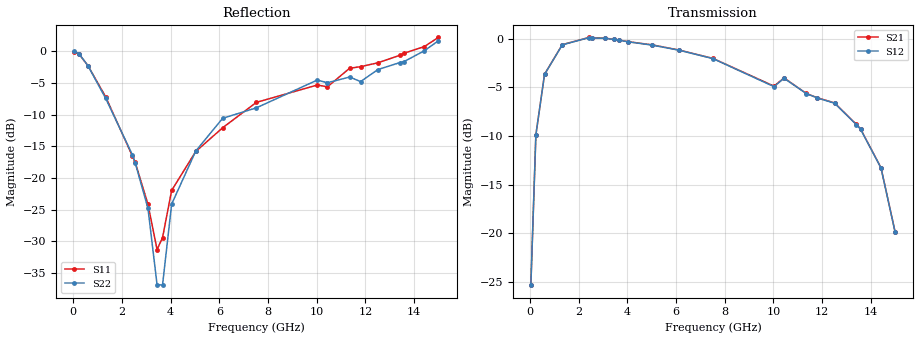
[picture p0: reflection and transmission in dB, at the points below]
! VJ1111D2R2BXR
! DATE 03/08/2022  10:55
! CAPACITORS MOUNTED IN SERIES ON 25 MIL THICK MICROSTRIP SUBSTRATE
# GHz  S  MA  R  50.00
!  FREQ  S11M  S11A  S21M  S21A  S12M  S12A  S22M  S22A
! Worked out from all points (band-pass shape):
!   801 points, 40 MHz to 15 GHz, reference 50 ohm
!   highest |S21| = 0.13 dB at 2.434 GHz (marker M1); lowest = -25.3 dB at 40 MHz (marker M2)
!   |S21| within 3 dB of the highest: 700.3 MHz to 8.719 GHz (8.019 GHz wide, 170 % of centre)
!   lowest |S11| = -31.3 dB at 3.443 GHz (marker M3), VSWR 1.06, Z = 47.7 - j1.24 ohm
!   |S11| at or under -10 dB: 1.71 GHz to 6.915 GHz (5.205 GHz wide, 121 % of centre)
!   |S22| runs from -38.9 to 1.7 dB; largest |S21 - S12| = 0.007
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0.04  0.9961 -3.1  0.05424 86.5  0.05463 86.1  1.004 -3.1
0.2457  0.9471 -18.2  0.3207 72.2  0.3207 72.3  0.9537 -18.2
0.601  0.7733 -39.9  0.6562 51.6  0.6551 51.6  0.773 -39.9
1.3303  0.4383 -65.6  0.9315 28.0  0.9291 28.0  0.4261 -66.8
2.4336  0.1483 -85.1  1.015 12.4  1.013 12.5  0.1517 -88.9
2.5458  0.1326 -87.6  1.012 11.4  1.009 11.4  0.1315 -91.1
3.0694  0.06191 -101.0  1.006 7.0  1.003 7.1  0.05745 -103.9
3.4434  0.02713 -151.4  0.9925 4.6  0.9904 4.7  0.0143 -134.7
3.6678  0.03369 149.6  0.9829 3.2  0.9808 3.3  0.0142 108.1
4.0418  0.07959 105.7  0.9647 2.1  0.9626 2.2  0.06204 91.5
5.0329  0.1619 85.9  0.9287 -2.9  0.926 -2.8  0.1632 72.4
6.1362  0.249 77.4  0.8738 -9.0  0.8717 -8.8  0.2959 62.7
7.52  0.3953 65.9  0.7915 -14.8  0.7895 -14.5  0.358 55.9
10.0258  0.5426 45.1  0.5702 -21.9  0.5668 -21.8  0.5938 35.5
10.4372  0.5245 53.3  0.6287 -20.8  0.6254 -20.9  0.5651 36.8
11.3535  0.7365 49.9  0.5231 -29.9  0.5225 -29.7  0.6274 24.5
11.8023  0.757 39.8  0.4975 -26.0  0.4958 -25.8  0.5774 31.3
12.5129  0.8134 33.5  0.4676 -33.9  0.4661 -33.7  0.7186 35.0
13.4105  0.9307 27.1  0.3628 -40.4  0.3616 -40.1  0.8154 30.1
13.5788  0.9665 -152.0  0.3443 -41.5  0.3426 -41.1  0.8297 -152.5
14.4203  1.092 -150.8  0.2173 -44.5  0.2168 -44.0  1.011 -165.5
15  1.291 -160.5  0.1017 -11.2  0.1015 -10.7  1.215 -174.4
